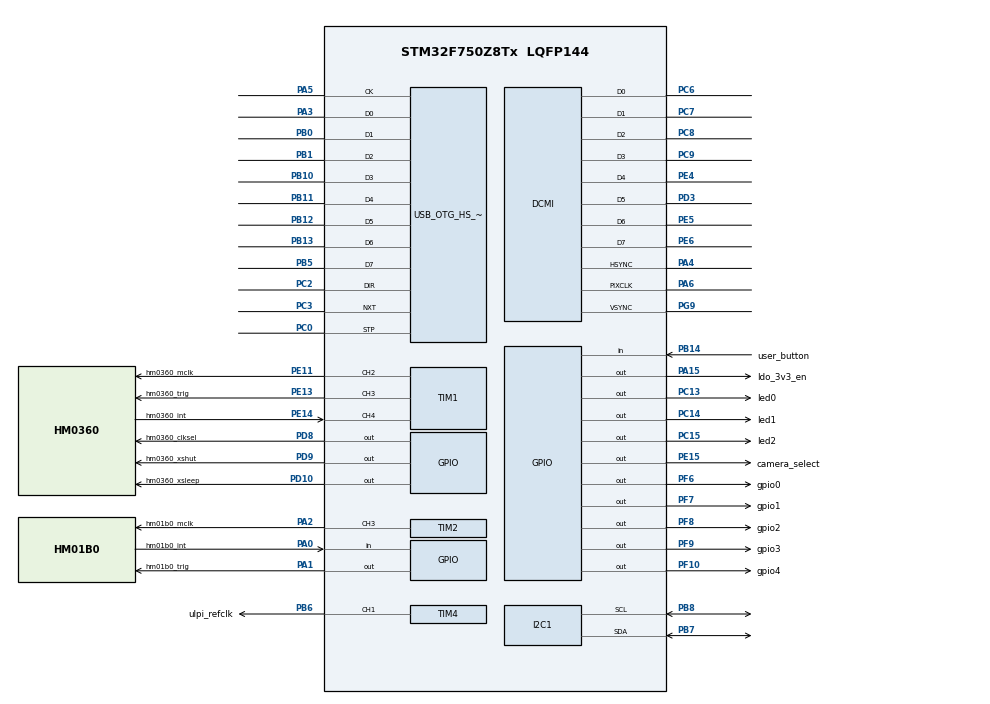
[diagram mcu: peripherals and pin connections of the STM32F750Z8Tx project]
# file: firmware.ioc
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FREERTOS.INCLUDE_vTaskDelayUntil=1
FREERTOS.MEMORY_ALLOCATION=1
FREERTOS.Tasks01=defaultTask,0,128,StartDefaultTask,Default,NULL,Static,defaultTaskBuffer,defaultTaskControlBlock
FREERTOS.configENABLE_FPU=1
FREERTOS.configUSE_COUNTING_SEMAPHORES=1
I2C1.Timing=0x20404768
Mcu.Family=STM32F7
Mcu.Name=STM32F750Z8Tx
Mcu.Package=LQFP144
NVIC.OTG_HS_IRQn=true\:5\:0\:false\:false\:true\:true\:false\:true\:true
NVIC.PriorityGroup=NVIC_PRIORITYGROUP_4
NVIC.TIM3_IRQn=true\:15\:0\:false\:false\:true\:false\:false\:true\:true
NVIC.TimeBase=TIM3_IRQn
NVIC.TimeBaseIP=TIM3
PA0/WKUP.GPIO_Label=hm01b0_int
PA0/WKUP.GPIO_PuPd=GPIO_PULLDOWN
PA0/WKUP.Signal=GPIO_Input
PA1.GPIO_Label=hm01b0_trig
PA1.Signal=GPIO_Output
PA13.Mode=Serial_Wire
PA13.Signal=SYS_JTMS-SWDIO
PA14.Mode=Serial_Wire
PA14.Signal=SYS_JTCK-SWCLK
PA15.GPIO_Label=ldo_3v3_en
PA15.Signal=GPIO_Output
PA2.GPIO_Label=hm01b0_mclk
PA2.GPIO_Speed=GPIO_SPEED_FREQ_HIGH
PA2.Signal=S_TIM2_CH3
PA3.Mode=Device_HS
PA3.Signal=USB_OTG_HS_ULPI_D0
PA4.Mode=Slave_8_bits_External_Synchro
PA4.Signal=DCMI_HSYNC
PA5.Mode=Device_HS
PA5.Signal=USB_OTG_HS_ULPI_CK
PA6.Mode=Slave_8_bits_External_Synchro
PA6.Signal=DCMI_PIXCLK
PB0.Mode=Device_HS
PB0.Signal=USB_OTG_HS_ULPI_D1
PB1.Mode=Device_HS
PB1.Signal=USB_OTG_HS_ULPI_D2
PB10.Mode=Device_HS
PB10.Signal=USB_OTG_HS_ULPI_D3
PB11.Mode=Device_HS
PB11.Signal=USB_OTG_HS_ULPI_D4
PB12.Mode=Device_HS
PB12.Signal=USB_OTG_HS_ULPI_D5
PB13.Mode=Device_HS
PB13.Signal=USB_OTG_HS_ULPI_D6
PB14.GPIO_Label=user_button
PB14.GPIO_PuPd=GPIO_PULLUP
PB14.Signal=GPIO_Input
PB3.Signal=SYS_JTDO-SWO
PB5.Mode=Device_HS
PB5.Signal=USB_OTG_HS_ULPI_D7
PB6.GPIO_Label=ulpi_refclk
PB6.GPIO_Speed=GPIO_SPEED_FREQ_HIGH
PB6.Signal=S_TIM4_CH1
PB7.Mode=I2C
PB7.Signal=I2C1_SDA
PB8.Mode=I2C
PB8.Signal=I2C1_SCL
PC0.Mode=Device_HS
PC0.Signal=USB_OTG_HS_ULPI_STP
PC13.GPIO_Label=led0
PC13.Signal=GPIO_Output
PC14/OSC32_IN.GPIO_Label=led1
PC14/OSC32_IN.Signal=GPIO_Output
PC15/OSC32_OUT.GPIO_Label=led2
PC15/OSC32_OUT.Signal=GPIO_Output
PC2.Mode=Device_HS
PC2.Signal=USB_OTG_HS_ULPI_DIR
PC3.Mode=Device_HS
PC3.Signal=USB_OTG_HS_ULPI_NXT
PC6.Mode=Slave_8_bits_External_Synchro
PC6.Signal=DCMI_D0
PC7.Mode=Slave_8_bits_External_Synchro
PC7.Signal=DCMI_D1
PC8.Mode=Slave_8_bits_External_Synchro
PC8.Signal=DCMI_D2
PC9.Mode=Slave_8_bits_External_Synchro
PC9.Signal=DCMI_D3
PD10.GPIO_Label=hm0360_xsleep
PD10.Signal=GPIO_Output
PD3.Mode=Slave_8_bits_External_Synchro
PD3.Signal=DCMI_D5
PD8.GPIO_Label=hm0360_clksel
PD8.Signal=GPIO_Output
PD9.GPIO_Label=hm0360_xshut
PD9.Signal=GPIO_Output
PE11.GPIO_Label=hm0360_mclk
PE11.GPIO_Speed=GPIO_SPEED_FREQ_HIGH
PE11.Signal=S_TIM1_CH2
PE13.GPIO_Label=hm0360_trig
PE13.Signal=S_TIM1_CH3
PE14.GPIO_Label=hm0360_int
PE14.Signal=S_TIM1_CH4
PE15.GPIO_Label=camera_select
PE15.Signal=GPIO_Output
PE4.Mode=Slave_8_bits_External_Synchro
PE4.Signal=DCMI_D4
PE5.Mode=Slave_8_bits_External_Synchro
PE5.Signal=DCMI_D6
PE6.Mode=Slave_8_bits_External_Synchro
PE6.Signal=DCMI_D7
PF10.GPIO_Label=gpio4
PF10.Signal=GPIO_Output
PF6.GPIO_Label=gpio0
PF6.Signal=GPIO_Output
PF7.GPIO_Label=gpio1
PF7.Signal=GPIO_Output
PF8.GPIO_Label=gpio2
PF8.Signal=GPIO_Output
PF9.GPIO_Label=gpio3
PF9.Signal=GPIO_Output
PG9.Mode=Slave_8_bits_External_Synchro
PG9.Signal=DCMI_VSYNC
PH0/OSC_IN.Mode=HSE-External-Oscillator
PH0/OSC_IN.Signal=RCC_OSC_IN
PH1/OSC_OUT.Mode=HSE-External-Oscillator
PH1/OSC_OUT.Signal=RCC_OSC_OUT
ProjectManager.HeapSize=0x200
ProjectManager.StackSize=0x400
ProjectManager.TargetToolchain=Makefile
RCC.AHBFreq_Value=216000000
RCC.APB1CLKDivider=RCC_HCLK_DIV4
RCC.APB1Freq_Value=54000000
RCC.APB1TimFreq_Value=108000000
RCC.APB2CLKDivider=RCC_HCLK_DIV2
RCC.APB2Freq_Value=108000000
RCC.APB2TimFreq_Value=216000000
RCC.CortexFreq_Value=216000000
RCC.HCLKFreq_Value=216000000
RCC.HSE_VALUE=12000000
RCC.HSI_VALUE=16000000
RCC.LSE_VALUE=32768
RCC.PLLM=8
RCC.PLLN=216
RCC.SYSCLKFreq_VALUE=216000000
RCC.SYSCLKSource=RCC_SYSCLKSOURCE_PLLCLK
RCC.USBFreq_Value=216000000
RCC.VCOOutputFreq_Value=432000000
SH.S_TIM1_CH2.0=TIM1_CH2,Output Compare2 CH2
SH.S_TIM1_CH3.0=TIM1_CH3,Output Compare3 CH3
SH.S_TIM1_CH4.0=TIM1_CH4,Input_Capture4_from_TI4
SH.S_TIM2_CH3.0=TIM2_CH3,PWM Generation3 CH3
SH.S_TIM4_CH1.0=TIM4_CH1,PWM Generation1 CH1
TIM1.Channel-Input_Capture4_from_TI4=TIM_CHANNEL_4
TIM1.Channel-Output\ Compare2\ CH2=TIM_CHANNEL_2
TIM1.Channel-Output\ Compare3\ CH3=TIM_CHANNEL_3
TIM2.Channel-PWM\ Generation3\ CH3=TIM_CHANNEL_3
TIM4.Channel-PWM\ Generation1\ CH1=TIM_CHANNEL_1
USB_DEVICE.CLASS_NAME_HS=CDC
USB_DEVICE.VirtualMode-CDC_HS=Cdc
USB_DEVICE.VirtualModeHS=Cdc_HS
USB_OTG_HS.VirtualMode-Device_HS=Device_HS
VP_FREERTOS_VS_CMSIS_V1.Mode=CMSIS_V1
VP_SYS_VS_tim3.Mode=TIM3
VP_TIM1_VS_ClockSourceINT.Mode=Internal
VP_TIM4_VS_ClockSourceINT.Mode=Internal
VP_USB_DEVICE_VS_USB_DEVICE_CDC_HS.Mode=CDC_HS
board=custom

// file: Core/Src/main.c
/* USER CODE BEGIN Header */
/**
  ******************************************************************************
  * @file           : main.c
  * @brief          : Main program body
  ******************************************************************************
  * @attention
  *
  * Copyright (c) 2024 STMicroelectronics.
  * All rights reserved.
  *
  * This software is licensed under terms that can be found in the LICENSE file
  * in the root directory of this software component.
  * If no LICENSE file comes with this software, it is provided AS-IS.
  *
  ******************************************************************************
  */
/* USER CODE END Header */
#include "main.h"
#include "cmsis_os.h"
#include "usb_device.h"

/* USER CODE BEGIN Includes */
#include "system_task.h"
#include "camera_task.h"
/* USER CODE END Includes */

DCMI_HandleTypeDef hdcmi;

I2C_HandleTypeDef hi2c1;

TIM_HandleTypeDef htim1;
TIM_HandleTypeDef htim2;
TIM_HandleTypeDef htim4;

osThreadId defaultTaskHandle;
uint32_t defaultTaskBuffer[ 128 ];
osStaticThreadDef_t defaultTaskControlBlock;
/* USER CODE BEGIN PV */

#define SYSTEM_TASK_BUFSZ 512
osThreadId systemTaskHandle;
uint32_t systemTaskBuffer[ SYSTEM_TASK_BUFSZ ];
osStaticThreadDef_t systemTaskControlBlock;

#define CAMERA_TASK_BUFSZ 512
osThreadId cameraTaskHandle;
uint32_t cameraTaskBuffer[ CAMERA_TASK_BUFSZ ];
osStaticThreadDef_t cameraTaskControlBlock;

/* USER CODE END PV */

void SystemClock_Config(void);
static void MX_GPIO_Init(void);
static void MX_DCMI_Init(void);
static void MX_I2C1_Init(void);
static void MX_TIM2_Init(void);
static void MX_TIM4_Init(void);
static void MX_TIM1_Init(void);
void StartDefaultTask(void const * argument);

int main(void)
{

  /* MCU Configuration--------------------------------------------------------*/

  /* Reset of all peripherals, Initializes the Flash interface and the Systick. */
  HAL_Init();

  /* Configure the system clock */
  SystemClock_Config();

  /* Initialize all configured peripherals */
  MX_GPIO_Init();
  MX_DCMI_Init();
  MX_I2C1_Init();
  MX_TIM2_Init();
  MX_TIM4_Init();
  MX_TIM1_Init();
  /* USER CODE BEGIN 2 */

  // enable 3v3 for ULPI transciever
  HAL_GPIO_WritePin(ldo_3v3_en_GPIO_Port, ldo_3v3_en_Pin, GPIO_PIN_SET);

  // Start ULPI refclk which is on TIM4 CH1, which is on APB1 and therefore has a frequency of
  // 96MHz.
  // REFSEL bits for ULPI refclk specify a 19.2MHz oscillator; we have a 192MHz sysclk, so we
  // can derive this from 96MHz. The USB3320C can tolerate a duty cycle of 20 - 80 % on its clock,
  // so it's ok to use TIM4 to divide 96MHz by 5, yielding a duty cycle of 40 or 60%.
  TIM4->CCER = 1;
  TIM4->CR1 |= (1 << 0);

  // should wait for a little bit after the timer is initialized to let the USB startup
  for (volatile int i = 0; i < 200000; i++);

  /* USER CODE END 2 */

  /* Create the thread(s) */
  /* definition and creation of defaultTask */
#if 1
  osThreadStaticDef(defaultTask, StartDefaultTask, osPriorityNormal, 0, 128, defaultTaskBuffer, &defaultTaskControlBlock);
  defaultTaskHandle = osThreadCreate(osThread(defaultTask), NULL);
#endif

  /* USER CODE BEGIN RTOS_THREADS */
  osThreadStaticDef(systemTask,
                    system_task,
                    osPriorityNormal,
                    0,
                    SYSTEM_TASK_BUFSZ,
                    systemTaskBuffer,
                    &systemTaskControlBlock);
  systemTaskHandle = osThreadCreate(osThread(systemTask), NULL);

#if 1
  osThreadStaticDef(cameraTask,
                    camera_task,
                    osPriorityNormal,
                    0,
                    CAMERA_TASK_BUFSZ,
                    cameraTaskBuffer,
                    &cameraTaskControlBlock);
  cameraTaskHandle = osThreadCreate(osThread(cameraTask), NULL);
#endif

  /* USER CODE END RTOS_THREADS */

  /* Start scheduler */
  osKernelStart();
  /* We should never get here as control is now taken by the scheduler */
  /* Infinite loop */
  while (1)
  {

  }
}

void SystemClock_Config(void)
{
  RCC_OscInitTypeDef RCC_OscInitStruct = {0};
  RCC_ClkInitTypeDef RCC_ClkInitStruct = {0};

  /** Configure the main internal regulator output voltage
  */
  __HAL_RCC_PWR_CLK_ENABLE();
  __HAL_PWR_VOLTAGESCALING_CONFIG(PWR_REGULATOR_VOLTAGE_SCALE1);

  /** Initializes the RCC Oscillators according to the specified parameters
  * in the RCC_OscInitTypeDef structure.
  */
  RCC_OscInitStruct.OscillatorType = RCC_OSCILLATORTYPE_HSE;
  RCC_OscInitStruct.HSEState = RCC_HSE_ON;
  RCC_OscInitStruct.PLL.PLLState = RCC_PLL_ON;
  RCC_OscInitStruct.PLL.PLLSource = RCC_PLLSOURCE_HSE;
  RCC_OscInitStruct.PLL.PLLM = 6;
  RCC_OscInitStruct.PLL.PLLN = 192;
  RCC_OscInitStruct.PLL.PLLP = RCC_PLLP_DIV2;
  RCC_OscInitStruct.PLL.PLLQ = 3;
  if (HAL_RCC_OscConfig(&RCC_OscInitStruct) != HAL_OK)
  {
    Error_Handler();
  }

  /** Activate the Over-Drive mode
  */
  if (HAL_PWREx_EnableOverDrive() != HAL_OK)
  {
    Error_Handler();
  }

  /** Initializes the CPU, AHB and APB buses clocks
  */
  RCC_ClkInitStruct.ClockType = RCC_CLOCKTYPE_HCLK|RCC_CLOCKTYPE_SYSCLK
                              |RCC_CLOCKTYPE_PCLK1|RCC_CLOCKTYPE_PCLK2;
  RCC_ClkInitStruct.SYSCLKSource = RCC_SYSCLKSOURCE_PLLCLK;
  RCC_ClkInitStruct.AHBCLKDivider = RCC_SYSCLK_DIV1;
  RCC_ClkInitStruct.APB1CLKDivider = RCC_HCLK_DIV4;
  RCC_ClkInitStruct.APB2CLKDivider = RCC_HCLK_DIV2;

  if (HAL_RCC_ClockConfig(&RCC_ClkInitStruct, FLASH_LATENCY_6) != HAL_OK)
  {
    Error_Handler();
  }
}

static void MX_DCMI_Init(void)
{

  hdcmi.Instance = DCMI;
  hdcmi.Init.SynchroMode = DCMI_SYNCHRO_HARDWARE;
  hdcmi.Init.PCKPolarity = DCMI_PCKPOLARITY_FALLING;
  hdcmi.Init.VSPolarity = DCMI_VSPOLARITY_LOW;
  hdcmi.Init.HSPolarity = DCMI_HSPOLARITY_LOW;
  hdcmi.Init.CaptureRate = DCMI_CR_ALL_FRAME;
  hdcmi.Init.ExtendedDataMode = DCMI_EXTEND_DATA_8B;
  hdcmi.Init.JPEGMode = DCMI_JPEG_DISABLE;
  hdcmi.Init.ByteSelectMode = DCMI_BSM_ALL;
  hdcmi.Init.ByteSelectStart = DCMI_OEBS_ODD;
  hdcmi.Init.LineSelectMode = DCMI_LSM_ALL;
  hdcmi.Init.LineSelectStart = DCMI_OELS_ODD;
  if (HAL_DCMI_Init(&hdcmi) != HAL_OK)
  {
    Error_Handler();
  }

}

static void MX_I2C1_Init(void)
{

  hi2c1.Instance = I2C1;
  hi2c1.Init.Timing = 0x20303E5D;
  hi2c1.Init.OwnAddress1 = 0;
  hi2c1.Init.AddressingMode = I2C_ADDRESSINGMODE_7BIT;
  hi2c1.Init.DualAddressMode = I2C_DUALADDRESS_DISABLE;
  hi2c1.Init.OwnAddress2 = 0;
  hi2c1.Init.OwnAddress2Masks = I2C_OA2_NOMASK;
  hi2c1.Init.GeneralCallMode = I2C_GENERALCALL_DISABLE;
  hi2c1.Init.NoStretchMode = I2C_NOSTRETCH_DISABLE;
  if (HAL_I2C_Init(&hi2c1) != HAL_OK)
  {
    Error_Handler();
  }

  /** Configure Analogue filter
  */
  if (HAL_I2CEx_ConfigAnalogFilter(&hi2c1, I2C_ANALOGFILTER_ENABLE) != HAL_OK)
  {
    Error_Handler();
  }

  /** Configure Digital filter
  */
  if (HAL_I2CEx_ConfigDigitalFilter(&hi2c1, 0) != HAL_OK)
  {
    Error_Handler();
  }

}

static void MX_TIM1_Init(void)
{

  TIM_ClockConfigTypeDef sClockSourceConfig = {0};
  TIM_MasterConfigTypeDef sMasterConfig = {0};
  TIM_OC_InitTypeDef sConfigOC = {0};
  TIM_IC_InitTypeDef sConfigIC = {0};
  TIM_BreakDeadTimeConfigTypeDef sBreakDeadTimeConfig = {0};

  htim1.Instance = TIM1;
  htim1.Init.Prescaler = 0;
  htim1.Init.CounterMode = TIM_COUNTERMODE_UP;
  htim1.Init.Period = 65535;
  htim1.Init.ClockDivision = TIM_CLOCKDIVISION_DIV1;
  htim1.Init.RepetitionCounter = 0;
  htim1.Init.AutoReloadPreload = TIM_AUTORELOAD_PRELOAD_DISABLE;
  if (HAL_TIM_Base_Init(&htim1) != HAL_OK)
  {
    Error_Handler();
  }
  sClockSourceConfig.ClockSource = TIM_CLOCKSOURCE_INTERNAL;
  if (HAL_TIM_ConfigClockSource(&htim1, &sClockSourceConfig) != HAL_OK)
  {
    Error_Handler();
  }
  if (HAL_TIM_OC_Init(&htim1) != HAL_OK)
  {
    Error_Handler();
  }
  if (HAL_TIM_IC_Init(&htim1) != HAL_OK)
  {
    Error_Handler();
  }
  sMasterConfig.MasterOutputTrigger = TIM_TRGO_RESET;
  sMasterConfig.MasterOutputTrigger2 = TIM_TRGO2_RESET;
  sMasterConfig.MasterSlaveMode = TIM_MASTERSLAVEMODE_DISABLE;
  if (HAL_TIMEx_MasterConfigSynchronization(&htim1, &sMasterConfig) != HAL_OK)
  {
    Error_Handler();
  }
  sConfigOC.OCMode = TIM_OCMODE_TIMING;
  sConfigOC.Pulse = 0;
  sConfigOC.OCPolarity = TIM_OCPOLARITY_HIGH;
  sConfigOC.OCNPolarity = TIM_OCNPOLARITY_HIGH;
  sConfigOC.OCFastMode = TIM_OCFAST_DISABLE;
  sConfigOC.OCIdleState = TIM_OCIDLESTATE_RESET;
  sConfigOC.OCNIdleState = TIM_OCNIDLESTATE_RESET;
  if (HAL_TIM_OC_ConfigChannel(&htim1, &sConfigOC, TIM_CHANNEL_2) != HAL_OK)
  {
    Error_Handler();
  }
  if (HAL_TIM_OC_ConfigChannel(&htim1, &sConfigOC, TIM_CHANNEL_3) != HAL_OK)
  {
    Error_Handler();
  }
  sConfigIC.ICPolarity = TIM_INPUTCHANNELPOLARITY_RISING;
  sConfigIC.ICSelection = TIM_ICSELECTION_DIRECTTI;
  sConfigIC.ICPrescaler = TIM_ICPSC_DIV1;
  sConfigIC.ICFilter = 0;
  if (HAL_TIM_IC_ConfigChannel(&htim1, &sConfigIC, TIM_CHANNEL_4) != HAL_OK)
  {
    Error_Handler();
  }
  sBreakDeadTimeConfig.OffStateRunMode = TIM_OSSR_DISABLE;
  sBreakDeadTimeConfig.OffStateIDLEMode = TIM_OSSI_DISABLE;
  sBreakDeadTimeConfig.LockLevel = TIM_LOCKLEVEL_OFF;
  sBreakDeadTimeConfig.DeadTime = 0;
  sBreakDeadTimeConfig.BreakState = TIM_BREAK_DISABLE;
  sBreakDeadTimeConfig.BreakPolarity = TIM_BREAKPOLARITY_HIGH;
  sBreakDeadTimeConfig.BreakFilter = 0;
  sBreakDeadTimeConfig.Break2State = TIM_BREAK2_DISABLE;
  sBreakDeadTimeConfig.Break2Polarity = TIM_BREAK2POLARITY_HIGH;
  sBreakDeadTimeConfig.Break2Filter = 0;
  sBreakDeadTimeConfig.AutomaticOutput = TIM_AUTOMATICOUTPUT_DISABLE;
  if (HAL_TIMEx_ConfigBreakDeadTime(&htim1, &sBreakDeadTimeConfig) != HAL_OK)
  {
    Error_Handler();
  }
  HAL_TIM_MspPostInit(&htim1);

}

static void MX_TIM2_Init(void)
{

  TIM_MasterConfigTypeDef sMasterConfig = {0};
  TIM_OC_InitTypeDef sConfigOC = {0};

  htim2.Instance = TIM2;
  htim2.Init.Prescaler = 0;
  htim2.Init.CounterMode = TIM_COUNTERMODE_UP;
  htim2.Init.Period = 7;
  htim2.Init.ClockDivision = TIM_CLOCKDIVISION_DIV1;
  htim2.Init.AutoReloadPreload = TIM_AUTORELOAD_PRELOAD_DISABLE;
  if (HAL_TIM_PWM_Init(&htim2) != HAL_OK)
  {
    Error_Handler();
  }
  sMasterConfig.MasterOutputTrigger = TIM_TRGO_RESET;
  sMasterConfig.MasterSlaveMode = TIM_MASTERSLAVEMODE_DISABLE;
  if (HAL_TIMEx_MasterConfigSynchronization(&htim2, &sMasterConfig) != HAL_OK)
  {
    Error_Handler();
  }
  sConfigOC.OCMode = TIM_OCMODE_PWM1;
  sConfigOC.Pulse = 4;
  sConfigOC.OCPolarity = TIM_OCPOLARITY_HIGH;
  sConfigOC.OCFastMode = TIM_OCFAST_DISABLE;
  if (HAL_TIM_PWM_ConfigChannel(&htim2, &sConfigOC, TIM_CHANNEL_3) != HAL_OK)
  {
    Error_Handler();
  }
  HAL_TIM_MspPostInit(&htim2);

}

static void MX_TIM4_Init(void)
{

  TIM_ClockConfigTypeDef sClockSourceConfig = {0};
  TIM_MasterConfigTypeDef sMasterConfig = {0};
  TIM_OC_InitTypeDef sConfigOC = {0};

  htim4.Instance = TIM4;
  htim4.Init.Prescaler = 0;
  htim4.Init.CounterMode = TIM_COUNTERMODE_UP;
  htim4.Init.Period = 4;
  htim4.Init.ClockDivision = TIM_CLOCKDIVISION_DIV1;
  htim4.Init.AutoReloadPreload = TIM_AUTORELOAD_PRELOAD_DISABLE;
  if (HAL_TIM_Base_Init(&htim4) != HAL_OK)
  {
    Error_Handler();
  }
  sClockSourceConfig.ClockSource = TIM_CLOCKSOURCE_INTERNAL;
  if (HAL_TIM_ConfigClockSource(&htim4, &sClockSourceConfig) != HAL_OK)
  {
    Error_Handler();
  }
  if (HAL_TIM_PWM_Init(&htim4) != HAL_OK)
  {
    Error_Handler();
  }
  sMasterConfig.MasterOutputTrigger = TIM_TRGO_RESET;
  sMasterConfig.MasterSlaveMode = TIM_MASTERSLAVEMODE_DISABLE;
  if (HAL_TIMEx_MasterConfigSynchronization(&htim4, &sMasterConfig) != HAL_OK)
  {
    Error_Handler();
  }
  sConfigOC.OCMode = TIM_OCMODE_PWM1;
  sConfigOC.Pulse = 2;
  sConfigOC.OCPolarity = TIM_OCPOLARITY_HIGH;
  sConfigOC.OCFastMode = TIM_OCFAST_ENABLE;
  if (HAL_TIM_PWM_ConfigChannel(&htim4, &sConfigOC, TIM_CHANNEL_1) != HAL_OK)
  {
    Error_Handler();
  }
  HAL_TIM_MspPostInit(&htim4);

}

static void MX_GPIO_Init(void)
{
  GPIO_InitTypeDef GPIO_InitStruct = {0};

  /* GPIO Ports Clock Enable */
  __HAL_RCC_GPIOE_CLK_ENABLE();
  __HAL_RCC_GPIOC_CLK_ENABLE();
  __HAL_RCC_GPIOF_CLK_ENABLE();
  __HAL_RCC_GPIOH_CLK_ENABLE();
  __HAL_RCC_GPIOA_CLK_ENABLE();
  __HAL_RCC_GPIOB_CLK_ENABLE();
  __HAL_RCC_GPIOD_CLK_ENABLE();
  __HAL_RCC_GPIOG_CLK_ENABLE();

  /*Configure GPIO pin Output Level */
  HAL_GPIO_WritePin(GPIOC, led0_Pin|led1_Pin|led2_Pin, GPIO_PIN_RESET);

  /*Configure GPIO pin Output Level */
  HAL_GPIO_WritePin(GPIOF, gpio0_Pin|gpio1_Pin|gpio2_Pin|gpio3_Pin
                          |gpio4_Pin, GPIO_PIN_RESET);

  /*Configure GPIO pin Output Level */
  HAL_GPIO_WritePin(GPIOA, hm01b0_trig_Pin|ldo_3v3_en_Pin, GPIO_PIN_RESET);

  /*Configure GPIO pin Output Level */
  HAL_GPIO_WritePin(camera_select_GPIO_Port, camera_select_Pin, GPIO_PIN_RESET);

  /*Configure GPIO pin Output Level */
  HAL_GPIO_WritePin(GPIOD, hm0360_clksel_Pin|hm0360_xshut_Pin|hm0360_xsleep_Pin, GPIO_PIN_RESET);

  /*Configure GPIO pins : led0_Pin led1_Pin led2_Pin */
  GPIO_InitStruct.Pin = led0_Pin|led1_Pin|led2_Pin;
  GPIO_InitStruct.Mode = GPIO_MODE_OUTPUT_PP;
  GPIO_InitStruct.Pull = GPIO_NOPULL;
  GPIO_InitStruct.Speed = GPIO_SPEED_FREQ_LOW;
  HAL_GPIO_Init(GPIOC, &GPIO_InitStruct);

  /*Configure GPIO pins : gpio0_Pin gpio1_Pin gpio2_Pin gpio3_Pin
                           gpio4_Pin */
  GPIO_InitStruct.Pin = gpio0_Pin|gpio1_Pin|gpio2_Pin|gpio3_Pin
                          |gpio4_Pin;
  GPIO_InitStruct.Mode = GPIO_MODE_OUTPUT_PP;
  GPIO_InitStruct.Pull = GPIO_NOPULL;
  GPIO_InitStruct.Speed = GPIO_SPEED_FREQ_LOW;
  HAL_GPIO_Init(GPIOF, &GPIO_InitStruct);

  /*Configure GPIO pin : hm01b0_int_Pin */
  GPIO_InitStruct.Pin = hm01b0_int_Pin;
  GPIO_InitStruct.Mode = GPIO_MODE_INPUT;
  GPIO_InitStruct.Pull = GPIO_PULLDOWN;
  HAL_GPIO_Init(hm01b0_int_GPIO_Port, &GPIO_InitStruct);

  /*Configure GPIO pins : hm01b0_trig_Pin ldo_3v3_en_Pin */
  GPIO_InitStruct.Pin = hm01b0_trig_Pin|ldo_3v3_en_Pin;
  GPIO_InitStruct.Mode = GPIO_MODE_OUTPUT_PP;
  GPIO_InitStruct.Pull = GPIO_NOPULL;
  GPIO_InitStruct.Speed = GPIO_SPEED_FREQ_LOW;
  HAL_GPIO_Init(GPIOA, &GPIO_InitStruct);

  /*Configure GPIO pin : camera_select_Pin */
  GPIO_InitStruct.Pin = camera_select_Pin;
  GPIO_InitStruct.Mode = GPIO_MODE_OUTPUT_PP;
  GPIO_InitStruct.Pull = GPIO_NOPULL;
  GPIO_InitStruct.Speed = GPIO_SPEED_FREQ_LOW;
  HAL_GPIO_Init(camera_select_GPIO_Port, &GPIO_InitStruct);

  /*Configure GPIO pin : user_button_Pin */
  GPIO_InitStruct.Pin = user_button_Pin;
  GPIO_InitStruct.Mode = GPIO_MODE_INPUT;
  GPIO_InitStruct.Pull = GPIO_PULLUP;
  HAL_GPIO_Init(user_button_GPIO_Port, &GPIO_InitStruct);

  /*Configure GPIO pins : hm0360_clksel_Pin hm0360_xshut_Pin hm0360_xsleep_Pin */
  GPIO_InitStruct.Pin = hm0360_clksel_Pin|hm0360_xshut_Pin|hm0360_xsleep_Pin;
  GPIO_InitStruct.Mode = GPIO_MODE_OUTPUT_PP;
  GPIO_InitStruct.Pull = GPIO_NOPULL;
  GPIO_InitStruct.Speed = GPIO_SPEED_FREQ_LOW;
  HAL_GPIO_Init(GPIOD, &GPIO_InitStruct);

}

const uint8_t* teststr =
    "0123456789abcdef0123456789abcdef0123456789abcdef0123456789abcdef"
    "0123456789abcdef0123456789abcdef0123456789abcdef0123456789abcdef"
    "0123456789abcdef0123456789abcdef0123456789abcdef0123456789abcdef"
    "0123456789abcdef0123456789abcdef0123456789abcdef0123456789abcdef"
    \
    "0123456789abcdef0123456789abcdef0123456789abcdef0123456789abcdef"
    "0123456789abcdef0123456789abcdef0123456789abcdef0123456789abcdef"
    "0123456789abcdef0123456789abcdef0123456789abcdef0123456789abcdef"
    "0123456789abcdef0123456789abcdef0123456789abcdef0123456789abcdef"
    \
    "0123456789abcdef0123456789abcdef0123456789abcdef0123456789abcdef"
    "0123456789abcdef0123456789abcdef0123456789abcdef0123456789abcdef"
    "0123456789abcdef0123456789abcdef0123456789abcdef0123456789abcdef"
    "0123456789abcdef0123456789abcdef0123456789abcdef0123456789abcdef"
    \
    "0123456789abcdef0123456789abcdef0123456789abcdef0123456789abcdef"
    "0123456789abcdef0123456789abcdef0123456789abcdef0123456789abcdef"
    "0123456789abcdef0123456789abcdef0123456789abcdef0123456789abcdef"
    "0123456789abcdef0123456789abcdef0123456789abcdef0123456789abcdef";
void StartDefaultTask(void const * argument)
{
  /* init code for USB_DEVICE */
  MX_USB_DEVICE_Init();
  /* USER CODE BEGIN 5 */
  /* Infinite loop */
  osDelay(100);
  for(;;)
  {
      // wait until

  //USBD_CDC_SetTxBuffer(&hUsbDeviceHS, STR, strlen(STR));
  //uint8_t rs = USBD_CDC_TransmitPacket(&hUsbDeviceHS);

      volatile uint32_t* backptr = (DMA2_Stream7->CR & (1 << 19)) ? DMA2_Stream7->M0AR : DMA2_Stream7->M1AR;
      extern uint8_t camerabuf[2][2 * 320 * 240];
      uint8_t rs = CDC_Transmit_HS(backptr, 2 * 320 * 240);

      HAL_GPIO_WritePin(led1_GPIO_Port, led1_Pin, GPIO_PIN_RESET);
      if ((rs == USBD_FAIL) || (rs == USBD_BUSY)) {
          HAL_GPIO_WritePin(led1_GPIO_Port, led1_Pin, GPIO_PIN_SET);
      }
      osDelay(100);
  }
  /* USER CODE END 5 */
}

void HAL_TIM_PeriodElapsedCallback(TIM_HandleTypeDef *htim)
{
  if (htim->Instance == TIM3) {
    HAL_IncTick();
  }
}

void Error_Handler(void)
{
  __disable_irq();
  while (1)
  {
  }
}
